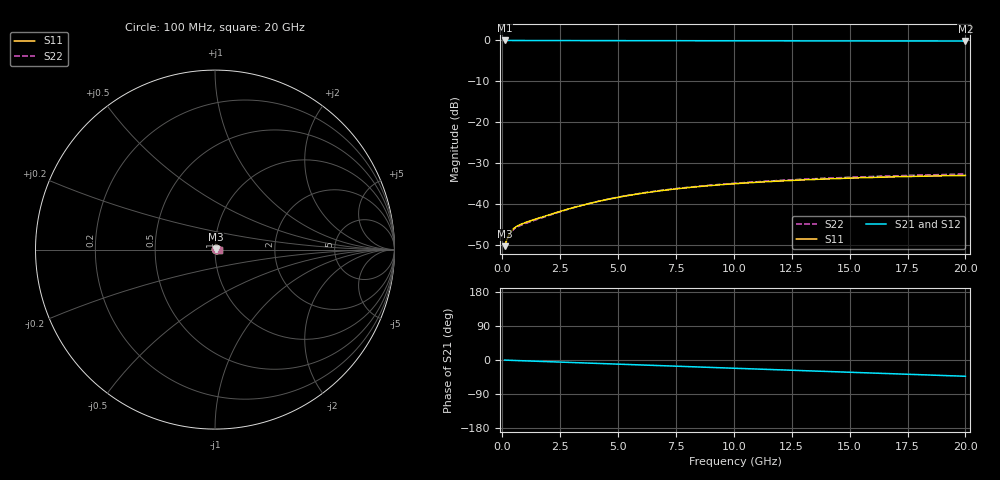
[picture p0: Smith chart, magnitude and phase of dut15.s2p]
! Touchstone file exported from HFSS 2026.1.0
!  File:  C:/ffzhzh/LocalFiles/Ansys_Project_Files/temp_test_BSMRDL_15_1782907422_13352.aedt
!  Generated:  08:04:49 PM Jul  1, 2026
!  Design:  BSMRDL
!  Project:  temp_test_BSMRDL_15_1782907422_13352
! Variables:
!  h_bsmrdl = 3.66um
!  h_ox = 20um
!  h_rdl = 5um
!  h_sub = 80um
!  h_tmrdl = 5um
!  h_tsv = 80um
!  h_via = 3um
!  l_bsmrdl = 760.8um
!  l_sub = 1160.8um
!  l_tmrdl = 200um
!  m_sub = 200um
!  pitch = 33.34um
!  r_tsv = 6um
!  s_tmrdl = 10um
!  w_bsmrdl = 28.26um
!  w_sub = 500um
!  w_tmrdl = 12um
!  x_tsv_center1 = 206um
!  x_tsv_center2 = 995.06um
!  x_tsv_center3 = 1207.06um
!  x_tsv_center4 = 1996.12um
!  x_tsv_center5 = 2208.12um
!  x_tsv_center6 = 2997.18um
# GHz S MA R 50.000000
! Terminal data exported
! Port[1] = BSM_RDL1_1_T1
! Port[2] = BSM_RDL1_1_T2
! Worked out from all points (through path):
!   200 points, 100 MHz to 20 GHz, reference 50 ohm
!   highest |S21| = -0.03 dB at 100 MHz (marker M1); lowest = -0.2 dB at 20 GHz (marker M2)
!   group delay of S21, straight-line fit = 5.94 ps
!   lowest |S11| = -50.2 dB at 100 MHz (marker M3), VSWR 1.01, Z = 50.3 + j0.0876 ohm
!   |S11| at or under -10 dB: start of sweep to end of sweep
!   |S22| runs from -50.2 to -32.6 dB; largest |S21 - S12| = 3.5e-15
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0.1  0.003098 16.3  0.997 -0.3  0.997 -0.3  0.003098 16.3
! Gamma 0 0 0 0
! Port Impedance 50 0 50 0
0.2  0.003727 23.9  0.9966 -0.5  0.9966 -0.5  0.003733 23.2
0.3  0.004314 25.9  0.9961 -0.7  0.9961 -0.7  0.004292 24.8
0.4  0.004763 26.1  0.9958 -1.0  0.9958 -1.0  0.004702 24.8
0.5  0.005096 25.9  0.9955 -1.2  0.9955 -1.2  0.005 24.7
0.6  0.005349 25.8  0.9953 -1.4  0.9953 -1.4  0.005227 24.7
0.7  0.005553 25.8  0.9951 -1.6  0.9951 -1.6  0.005412 24.9
0.9  0.005881 26.5  0.9949 -2.0  0.9949 -2.0  0.005722 25.9
1.1  0.006163 27.5  0.9948 -2.5  0.9948 -2.5  0.006001 27.2
1.9  0.007288 32.3  0.9942 -4.2  0.9942 -4.2  0.007173 32.4
2.7  0.00854 35.3  0.9936 -6.0  0.9936 -6.0  0.008486 35.4
3.5  0.009848 36.3  0.9929 -7.7  0.9929 -7.7  0.009845 36.2
4.2  0.01098 36.0  0.9922 -9.3  0.9922 -9.3  0.01101 35.8
5  0.01221 34.9  0.9914 -11.0  0.9914 -11.0  0.01227 34.5
5.9  0.01349 32.9  0.9904 -13.0  0.9904 -13.0  0.01357 32.4
6.8  0.01465 30.6  0.9895 -14.9  0.9895 -14.9  0.01476 30.1
8.3  0.01632 26.5  0.988 -18.1  0.988 -18.1  0.01647 25.8
10.1  0.01794 21.4  0.9864 -21.9  0.9864 -21.9  0.01817 20.6
11.7  0.01911 17.1  0.9851 -25.3  0.9851 -25.3  0.01941 16.0
13.4  0.02012 12.6  0.9839 -29.0  0.9839 -29.0  0.02053 11.3
16.7  0.0216 4.3  0.9818 -36.0  0.9818 -36.0  0.02221 2.6
20  0.02256 -3.6  0.9799 -42.9  0.9799 -42.9  0.02343 -5.8
